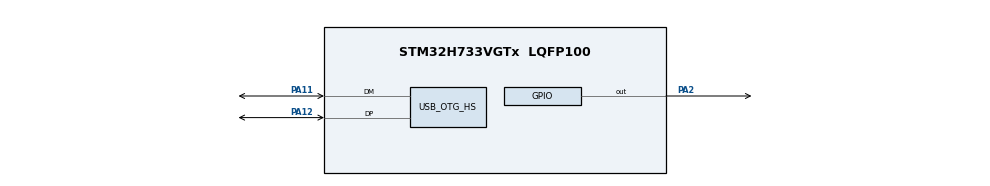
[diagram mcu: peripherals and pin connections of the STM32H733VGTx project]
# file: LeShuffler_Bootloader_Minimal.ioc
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CORTEX_M7.default_mode_Activation=1
Mcu.Family=STM32H7
Mcu.Name=STM32H733VGTx
Mcu.Package=LQFP100
NVIC.OTG_HS_IRQn=true\:0\:0\:false\:false\:true\:false\:true\:true
NVIC.PriorityGroup=NVIC_PRIORITYGROUP_4
PA11.Mode=Device_Only_FS
PA11.Signal=USB_OTG_HS_DM
PA12.Mode=Device_Only_FS
PA12.Signal=USB_OTG_HS_DP
PA2.Signal=GPIO_Output
ProjectManager.HeapSize=0x200
ProjectManager.StackSize=0x400
ProjectManager.TargetToolchain=STM32CubeIDE
RCC.ADCFreq_Value=129000000
RCC.APB1Freq_Value=64000000
RCC.APB2Freq_Value=64000000
RCC.APB3Freq_Value=64000000
RCC.APB4Freq_Value=64000000
RCC.CortexFreq_Value=64000000
RCC.HCLKFreq_Value=64000000
RCC.SYSCLKFreq_VALUE=64000000
RCC.USBCLockSelection=RCC_USBCLKSOURCE_HSI48
RCC.USBFreq_Value=48000000
USB_DEVICE.CLASS_NAME_HS=CDC
USB_DEVICE.VirtualMode=Cdc
USB_DEVICE.VirtualModeHS=Cdc_HS
USB_OTG_HS.VirtualMode-Device_Only_FS=Device_Only_FS
VP_CRC_VS_CRC.Mode=CRC_Activate
VP_MEMORYMAP_VS_MEMORYMAP.Mode=CurAppReg
VP_RTC_VS_RTC_Activate.Mode=RTC_Enabled
VP_USB_DEVICE_VS_USB_DEVICE_CDC_HS.Mode=CDC_HS
board=custom

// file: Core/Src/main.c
/* USER CODE BEGIN Header */
/**
  ******************************************************************************
  * @file           : main.c
  * @brief          : Main program body
  ******************************************************************************
  * @attention
  *
  * Copyright (c) 2025 STMicroelectronics.
  * All rights reserved.
  *
  * This software is licensed under terms that can be found in the LICENSE file
  * in the root directory of this software component.
  * If no LICENSE file comes with this software, it is provided AS-IS.
  *
  ******************************************************************************
  */
/* USER CODE END Header */
#include "main.h"
#include "crc.h"
#include "rtc.h"
#include "usb_device.h"
#include "gpio.h"

/* USER CODE BEGIN Includes */
#include "bootload.h"
#include "usbd_cdc_if.h"
/* USER CODE END Includes */

/* USER CODE BEGIN PD */
#define BOOTLOADER_TIMEOUT_MS  30000  // 30 second timeout
#define APPLICATION_ADDRESS    0x08020000  // Sector 1 (128KB offset)
/* USER CODE END PD */

void SystemClock_Config(void);
static void MPU_Config(void);

int main(void)
{
  /* USER CODE BEGIN 1 */
  uint8_t bootloader_requested = 0;
  uint8_t application_valid = 0;
  uint32_t bootloader_timeout = BOOTLOADER_TIMEOUT_MS;

  // *** EARLIEST POSSIBLE CHECK: Jump to app BEFORE any peripheral/MPU init ***
  // This ensures the app starts in a clean state (no MPU, no HAL, no peripherals)
  // NOTE: IsBootloaderModeRequested() clears the flag, so save the result!
  {
      bootloader_requested = IsBootloaderModeRequested();  // Save result for later use
      uint32_t early_app_stack = *((uint32_t *)APPLICATION_ADDRESS);
      uint8_t early_app_valid = ((early_app_stack & 0xFFF00000) == 0x20000000 ||
                                  (early_app_stack & 0xFFF00000) == 0x24000000);

      // If no bootloader requested and valid app exists, jump immediately
      if (!bootloader_requested && early_app_valid) {
          JumpToApplication();
          // Never returns
      }
  }

  /* USER CODE END 1 */

  /* MPU Configuration--------------------------------------------------------*/
  MPU_Config();

  /* MCU Configuration--------------------------------------------------------*/

  /* Reset of all peripherals, Initializes the Flash interface and the Systick. */
  HAL_Init();

  /* Configure the system clock */
  SystemClock_Config();

  /* Initialize all configured peripherals */
  MX_GPIO_Init();
  MX_CRC_Init();
  MX_RTC_Init();

  // Check if valid application exists (stack pointer in RAM region)
  uint32_t app_stack = *((uint32_t *)APPLICATION_ADDRESS);
  application_valid = ((app_stack & 0xFFF00000) == 0x20000000 ||
                       (app_stack & 0xFFF00000) == 0x24000000) ? 1 : 0;

  // Erase flash BEFORE USB init (USB dies during erase operations)
  if (bootloader_requested || !application_valid) {
      // 3 short beeps = entering bootloader mode
      for (int i = 0; i < 3; i++) {
          HAL_GPIO_WritePin(GPIOA, GPIO_PIN_2, GPIO_PIN_SET);
          HAL_Delay(100);
          HAL_GPIO_WritePin(GPIOA, GPIO_PIN_2, GPIO_PIN_RESET);
          HAL_Delay(100);
      }

      // Erase application flash (sectors 1-7, 896KB)
      EraseApplicationFlash();

      // 1 long beep = ready for firmware transfer
      HAL_GPIO_WritePin(GPIOA, GPIO_PIN_2, GPIO_PIN_SET);
      HAL_Delay(500);
      HAL_GPIO_WritePin(GPIOA, GPIO_PIN_2, GPIO_PIN_RESET);
  }

  // Initialize USB after flash erase is complete
  MX_USB_DEVICE_Init();

  /* Infinite loop */
  while (1)
  {

    /* USER CODE BEGIN 3 */

    // Process any received packets (do flash operations here, not in interrupt)
    CDC_ProcessPacket();

    // Check firmware update state
    FirmwareUpdateState_t fw_state = GetFirmwareUpdateState();

    if (fw_state == FW_ERROR) {
        // Error occurred - reset state and continue waiting
        ResetFirmwareUpdate();

        // Give error feedback (fast beeps)
        for (int i = 0; i < 5; i++) {
            HAL_GPIO_WritePin(GPIOA, GPIO_PIN_2, GPIO_PIN_SET);
            HAL_Delay(50);
            HAL_GPIO_WritePin(GPIOA, GPIO_PIN_2, GPIO_PIN_RESET);
            HAL_Delay(50);
        }
    }

    if (fw_state == FW_COMPLETE) {
        // Firmware update complete - do success beeps then reset

        // SUCCESS: 2 long beeps = about to reset
        for (int i = 0; i < 2; i++) {
            HAL_GPIO_WritePin(GPIOA, GPIO_PIN_2, GPIO_PIN_SET);
            HAL_Delay(500);
            HAL_GPIO_WritePin(GPIOA, GPIO_PIN_2, GPIO_PIN_RESET);
            HAL_Delay(300);
        }

        // Disable interrupts before reset to prevent any interference
        __disable_irq();

        // Small delay to ensure all pending operations complete
        for (volatile uint32_t i = 0; i < 1000000; i++);

        // Reset to run new application
        NVIC_SystemReset();

        // Should never reach here
        while(1);
    }

    // Timeout handling - if no firmware received, jump to application
    if (bootloader_timeout > 0) {
        HAL_Delay(10);
        bootloader_timeout -= 10;
    } else {
        // Timeout expired
        if (application_valid) {
            // Jump to application
            JumpToApplication();
        } else {
            // No application - stay in bootloader forever
            bootloader_timeout = BOOTLOADER_TIMEOUT_MS;  // Reset timeout
        }
    }

    // Reset timeout if firmware update is in progress
    if (fw_state == FW_RECEIVING) {
        bootloader_timeout = BOOTLOADER_TIMEOUT_MS;
    }
  }
  /* USER CODE END 3 */
}

void SystemClock_Config(void)
{
  RCC_OscInitTypeDef RCC_OscInitStruct = {0};
  RCC_ClkInitTypeDef RCC_ClkInitStruct = {0};

  /** Supply configuration update enable
  */
  HAL_PWREx_ConfigSupply(PWR_LDO_SUPPLY);

  /** Configure the main internal regulator output voltage
  */
  __HAL_PWR_VOLTAGESCALING_CONFIG(PWR_REGULATOR_VOLTAGE_SCALE3);

  while(!__HAL_PWR_GET_FLAG(PWR_FLAG_VOSRDY)) {}

  /** Initializes the RCC Oscillators according to the specified parameters
  * in the RCC_OscInitTypeDef structure.
  * MATCHED TO MAIN FIRMWARE for USB stability
  */
  RCC_OscInitStruct.OscillatorType = RCC_OSCILLATORTYPE_HSI48|RCC_OSCILLATORTYPE_HSI
                              |RCC_OSCILLATORTYPE_LSI;
  RCC_OscInitStruct.HSIState = RCC_HSI_DIV1;
  RCC_OscInitStruct.HSICalibrationValue = 64;
  RCC_OscInitStruct.LSIState = RCC_LSI_ON;
  RCC_OscInitStruct.HSI48State = RCC_HSI48_ON;
  RCC_OscInitStruct.PLL.PLLState = RCC_PLL_ON;
  RCC_OscInitStruct.PLL.PLLSource = RCC_PLLSOURCE_HSI;
  RCC_OscInitStruct.PLL.PLLM = 4;
  RCC_OscInitStruct.PLL.PLLN = 12;
  RCC_OscInitStruct.PLL.PLLP = 3;
  RCC_OscInitStruct.PLL.PLLQ = 2;
  RCC_OscInitStruct.PLL.PLLR = 2;
  RCC_OscInitStruct.PLL.PLLRGE = RCC_PLL1VCIRANGE_3;
  RCC_OscInitStruct.PLL.PLLVCOSEL = RCC_PLL1VCOWIDE;
  RCC_OscInitStruct.PLL.PLLFRACN = 0;
  if (HAL_RCC_OscConfig(&RCC_OscInitStruct) != HAL_OK)
  {
    Error_Handler();
  }

  /** Initializes the CPU, AHB and APB buses clocks
  * MATCHED TO MAIN FIRMWARE for USB stability
  */
  RCC_ClkInitStruct.ClockType = RCC_CLOCKTYPE_HCLK|RCC_CLOCKTYPE_SYSCLK
                              |RCC_CLOCKTYPE_PCLK1|RCC_CLOCKTYPE_PCLK2
                              |RCC_CLOCKTYPE_D3PCLK1|RCC_CLOCKTYPE_D1PCLK1;
  RCC_ClkInitStruct.SYSCLKSource = RCC_SYSCLKSOURCE_PLLCLK;
  RCC_ClkInitStruct.SYSCLKDivider = RCC_SYSCLK_DIV1;
  RCC_ClkInitStruct.AHBCLKDivider = RCC_HCLK_DIV1;
  RCC_ClkInitStruct.APB3CLKDivider = RCC_APB3_DIV2;
  RCC_ClkInitStruct.APB1CLKDivider = RCC_APB1_DIV2;
  RCC_ClkInitStruct.APB2CLKDivider = RCC_APB2_DIV2;
  RCC_ClkInitStruct.APB4CLKDivider = RCC_APB4_DIV2;

  if (HAL_RCC_ClockConfig(&RCC_ClkInitStruct, FLASH_LATENCY_1) != HAL_OK)
  {
    Error_Handler();
  }
}

 /* MPU Configuration */

void MPU_Config(void)
{
  MPU_Region_InitTypeDef MPU_InitStruct = {0};

  /* Disables the MPU */
  HAL_MPU_Disable();

  /** Initializes and configures the Region and the memory to be protected
  */
  MPU_InitStruct.Enable = MPU_REGION_ENABLE;
  MPU_InitStruct.Number = MPU_REGION_NUMBER0;
  MPU_InitStruct.BaseAddress = 0x0;
  MPU_InitStruct.Size = MPU_REGION_SIZE_4GB;
  MPU_InitStruct.SubRegionDisable = 0x87;
  MPU_InitStruct.TypeExtField = MPU_TEX_LEVEL0;
  MPU_InitStruct.AccessPermission = MPU_REGION_NO_ACCESS;
  MPU_InitStruct.DisableExec = MPU_INSTRUCTION_ACCESS_DISABLE;
  MPU_InitStruct.IsShareable = MPU_ACCESS_SHAREABLE;
  MPU_InitStruct.IsCacheable = MPU_ACCESS_NOT_CACHEABLE;
  MPU_InitStruct.IsBufferable = MPU_ACCESS_NOT_BUFFERABLE;

  HAL_MPU_ConfigRegion(&MPU_InitStruct);
  /* Enables the MPU */
  HAL_MPU_Enable(MPU_PRIVILEGED_DEFAULT);

}

void Error_Handler(void)
{
  __disable_irq();
  while (1)
  {
  }
}
